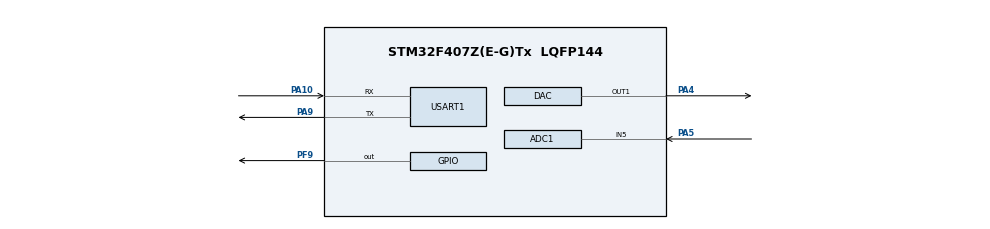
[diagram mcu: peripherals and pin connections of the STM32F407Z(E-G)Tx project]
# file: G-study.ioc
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ADC1.Channel-0\#ChannelRegularConversion=ADC_CHANNEL_5
ADC1.NbrOfConversionFlag=1
ADC1.Rank-0\#ChannelRegularConversion=1
ADC1.SamplingTime-0\#ChannelRegularConversion=ADC_SAMPLETIME_480CYCLES
ADC1.master=1
DAC.DAC_OutputBuffer=DAC_OUTPUTBUFFER_DISABLE
DAC.DAC_Trigger=DAC_TRIGGER_T6_TRGO
Dma.DAC1.0.Direction=DMA_MEMORY_TO_PERIPH
Dma.DAC1.0.FIFOMode=DMA_FIFOMODE_DISABLE
Dma.DAC1.0.Instance=DMA1_Stream5
Dma.DAC1.0.MemDataAlignment=DMA_MDATAALIGN_HALFWORD
Dma.DAC1.0.MemInc=DMA_MINC_ENABLE
Dma.DAC1.0.Mode=DMA_CIRCULAR
Dma.DAC1.0.PeriphDataAlignment=DMA_PDATAALIGN_HALFWORD
Dma.DAC1.0.PeriphInc=DMA_PINC_DISABLE
Dma.DAC1.0.Priority=DMA_PRIORITY_HIGH
Dma.Request0=DAC1
Mcu.Family=STM32F4
Mcu.Name=STM32F407Z(E-G)Tx
Mcu.Package=LQFP144
NVIC.DMA1_Stream5_IRQn=true\:0\:0\:false\:false\:true\:false\:true\:true
NVIC.PriorityGroup=NVIC_PRIORITYGROUP_4
NVIC.USART1_IRQn=true\:0\:0\:false\:false\:true\:true\:true\:true
PA10.Mode=Asynchronous
PA10.Signal=USART1_RX
PA4.Signal=COMP_DAC1_group
PA5.Signal=ADCx_IN5
PA9.Mode=Asynchronous
PA9.Signal=USART1_TX
PF9.PinState=GPIO_PIN_SET
PF9.Signal=GPIO_Output
PH0-OSC_IN.Mode=HSE-External-Oscillator
PH0-OSC_IN.Signal=RCC_OSC_IN
PH1-OSC_OUT.Mode=HSE-External-Oscillator
PH1-OSC_OUT.Signal=RCC_OSC_OUT
ProjectManager.HeapSize=0x200
ProjectManager.StackSize=0x400
ProjectManager.TargetToolchain=STM32CubeIDE
RCC.48MHZClocksFreq_Value=84000000
RCC.AHBFreq_Value=168000000
RCC.APB1CLKDivider=RCC_HCLK_DIV4
RCC.APB1Freq_Value=42000000
RCC.APB1TimFreq_Value=84000000
RCC.APB2CLKDivider=RCC_HCLK_DIV2
RCC.APB2Freq_Value=84000000
RCC.APB2TimFreq_Value=168000000
RCC.CortexFreq_Value=168000000
RCC.HCLKFreq_Value=168000000
RCC.HSE_VALUE=8000000
RCC.HSI_VALUE=16000000
RCC.LSE_VALUE=32768
RCC.PLLM=8
RCC.PLLN=336
RCC.PLLSourceVirtual=RCC_PLLSOURCE_HSE
RCC.SYSCLKFreq_VALUE=168000000
RCC.SYSCLKSource=RCC_SYSCLKSOURCE_PLLCLK
RCC.VCOOutputFreq_Value=336000000
SH.ADCx_IN5.0=ADC1_IN5,IN5
SH.COMP_DAC1_group.0=DAC_OUT1,DAC_OUT1
TIM6.AutoReloadPreload=TIM_AUTORELOAD_PRELOAD_ENABLE
TIM6.Period=99
TIM6.Prescaler=83
TIM6.TIM_MasterOutputTrigger=TIM_TRGO_UPDATE
USART1.VirtualMode=VM_ASYNC
VP_TIM6_VS_ClockSourceINT.Mode=Enable_Timer
board=custom

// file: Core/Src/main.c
/* USER CODE BEGIN Header */
/**
  ******************************************************************************
  * @file           : main.c
  * @brief          : Main program body
  ******************************************************************************
  * @attention
  *
  * Copyright (c) 2026 STMicroelectronics.
  * All rights reserved.
  *
  * This software is licensed under terms that can be found in the LICENSE file
  * in the root directory of this software component.
  * If no LICENSE file comes with this software, it is provided AS-IS.
  *
  ******************************************************************************
  */
/* USER CODE END Header */
#include "main.h"

ADC_HandleTypeDef hadc1;

DAC_HandleTypeDef hdac;
DMA_HandleTypeDef hdma_dac1;

TIM_HandleTypeDef htim6;

UART_HandleTypeDef huart1;

void SystemClock_Config(void);
static void MX_GPIO_Init(void);
static void MX_DMA_Init(void);
static void MX_DAC_Init(void);
static void MX_TIM6_Init(void);
static void MX_USART1_UART_Init(void);
static void MX_ADC1_Init(void);

int main(void)
{

/* USER CODE BEGIN 1 */
  RCC->AHB1ENR |= (1 << 5);
  GPIOF->MODER = (GPIOF->MODER & ~(3 << 18)) | (1 << 18);
  while(1) {
    GPIOF->ODR ^= (1 << 9);
    for(volatile int i = 0; i < 2000000; i++);
  }
  RCC->AHB1ENR |= (1 << 5);
  GPIOF->MODER = (GPIOF->MODER & ~(3 << 18)) | (1 << 18);
  GPIOF->ODR &= ~(1 << 9);

  /* USER CODE END 1 */

  /* MCU Configuration--------------------------------------------------------*/

  /* Reset of all peripherals, Initializes the Flash interface and the Systick. */
  HAL_Init();

  /* Configure the system clock */
  SystemClock_Config();

  /* Initialize all configured peripherals */
  MX_GPIO_Init();
  MX_DMA_Init();
  MX_DAC_Init();
  MX_TIM6_Init();
  MX_USART1_UART_Init();
  MX_ADC1_Init();
  /* USER CODE BEGIN 2 */
  RCC->AHB1ENR |= (1 << 5);
  GPIOF->MODER = (GPIOF->MODER & ~(3 << 18)) | (1 << 18);
  while(1) {
    GPIOF->ODR ^= (1 << 9);
    for(volatile int i = 0; i < 2000000; i++);
  }
  /* USER CODE END 2 */

  /* Infinite loop */
  while (1)
  {

  }
}

void SystemClock_Config(void)
{
  RCC_OscInitTypeDef RCC_OscInitStruct = {0};
  RCC_ClkInitTypeDef RCC_ClkInitStruct = {0};

  /** Configure the main internal regulator output voltage
  */
  __HAL_RCC_PWR_CLK_ENABLE();
  __HAL_PWR_VOLTAGESCALING_CONFIG(PWR_REGULATOR_VOLTAGE_SCALE1);

  /** Initializes the RCC Oscillators according to the specified parameters
  * in the RCC_OscInitTypeDef structure.
  */
  RCC_OscInitStruct.OscillatorType = RCC_OSCILLATORTYPE_HSI;
  RCC_OscInitStruct.HSIState = RCC_HSI_ON;
  RCC_OscInitStruct.HSICalibrationValue = RCC_HSICALIBRATION_DEFAULT;
  RCC_OscInitStruct.PLL.PLLState = RCC_PLL_NONE;
  if (HAL_RCC_OscConfig(&RCC_OscInitStruct) != HAL_OK)
  {
    Error_Handler();
  }

  /** Initializes the CPU, AHB and APB buses clocks
  */
  RCC_ClkInitStruct.ClockType = RCC_CLOCKTYPE_HCLK|RCC_CLOCKTYPE_SYSCLK
                              |RCC_CLOCKTYPE_PCLK1|RCC_CLOCKTYPE_PCLK2;
  RCC_ClkInitStruct.SYSCLKSource = RCC_SYSCLKSOURCE_HSI;
  RCC_ClkInitStruct.AHBCLKDivider = RCC_SYSCLK_DIV1;
  RCC_ClkInitStruct.APB1CLKDivider = RCC_HCLK_DIV4;
  RCC_ClkInitStruct.APB2CLKDivider = RCC_HCLK_DIV2;

  if (HAL_RCC_ClockConfig(&RCC_ClkInitStruct, FLASH_LATENCY_0) != HAL_OK)
  {
    Error_Handler();
  }
}

static void MX_ADC1_Init(void)
{

  ADC_ChannelConfTypeDef sConfig = {0};

  /** Configure the global features of the ADC (Clock, Resolution, Data Alignment and number of conversion)
  */
  hadc1.Instance = ADC1;
  hadc1.Init.ClockPrescaler = ADC_CLOCK_SYNC_PCLK_DIV2;
  hadc1.Init.Resolution = ADC_RESOLUTION_12B;
  hadc1.Init.ScanConvMode = DISABLE;
  hadc1.Init.ContinuousConvMode = DISABLE;
  hadc1.Init.DiscontinuousConvMode = DISABLE;
  hadc1.Init.ExternalTrigConvEdge = ADC_EXTERNALTRIGCONVEDGE_NONE;
  hadc1.Init.ExternalTrigConv = ADC_SOFTWARE_START;
  hadc1.Init.DataAlign = ADC_DATAALIGN_RIGHT;
  hadc1.Init.NbrOfConversion = 1;
  hadc1.Init.DMAContinuousRequests = DISABLE;
  hadc1.Init.EOCSelection = ADC_EOC_SINGLE_CONV;
  if (HAL_ADC_Init(&hadc1) != HAL_OK)
  {
    Error_Handler();
  }

  /** Configure for the selected ADC regular channel its corresponding rank in the sequencer and its sample time.
  */
  sConfig.Channel = ADC_CHANNEL_5;
  sConfig.Rank = 1;
  sConfig.SamplingTime = ADC_SAMPLETIME_480CYCLES;
  if (HAL_ADC_ConfigChannel(&hadc1, &sConfig) != HAL_OK)
  {
    Error_Handler();
  }

}

static void MX_DAC_Init(void)
{

  DAC_ChannelConfTypeDef sConfig = {0};

  /** DAC Initialization
  */
  hdac.Instance = DAC;
  if (HAL_DAC_Init(&hdac) != HAL_OK)
  {
    Error_Handler();
  }

  /** DAC channel OUT1 config
  */
  sConfig.DAC_Trigger = DAC_TRIGGER_T6_TRGO;
  sConfig.DAC_OutputBuffer = DAC_OUTPUTBUFFER_DISABLE;
  if (HAL_DAC_ConfigChannel(&hdac, &sConfig, DAC_CHANNEL_1) != HAL_OK)
  {
    Error_Handler();
  }

}

static void MX_TIM6_Init(void)
{

  TIM_MasterConfigTypeDef sMasterConfig = {0};

  htim6.Instance = TIM6;
  htim6.Init.Prescaler = 83;
  htim6.Init.CounterMode = TIM_COUNTERMODE_UP;
  htim6.Init.Period = 99;
  htim6.Init.AutoReloadPreload = TIM_AUTORELOAD_PRELOAD_ENABLE;
  if (HAL_TIM_Base_Init(&htim6) != HAL_OK)
  {
    Error_Handler();
  }
  sMasterConfig.MasterOutputTrigger = TIM_TRGO_UPDATE;
  sMasterConfig.MasterSlaveMode = TIM_MASTERSLAVEMODE_DISABLE;
  if (HAL_TIMEx_MasterConfigSynchronization(&htim6, &sMasterConfig) != HAL_OK)
  {
    Error_Handler();
  }

}

static void MX_USART1_UART_Init(void)
{

  huart1.Instance = USART1;
  huart1.Init.BaudRate = 115200;
  huart1.Init.WordLength = UART_WORDLENGTH_8B;
  huart1.Init.StopBits = UART_STOPBITS_1;
  huart1.Init.Parity = UART_PARITY_NONE;
  huart1.Init.Mode = UART_MODE_TX_RX;
  huart1.Init.HwFlowCtl = UART_HWCONTROL_NONE;
  huart1.Init.OverSampling = UART_OVERSAMPLING_16;
  if (HAL_UART_Init(&huart1) != HAL_OK)
  {
    Error_Handler();
  }

}

static void MX_DMA_Init(void)
{

  /* DMA controller clock enable */
  __HAL_RCC_DMA1_CLK_ENABLE();

  /* DMA interrupt init */
  /* DMA1_Stream5_IRQn interrupt configuration */
  HAL_NVIC_SetPriority(DMA1_Stream5_IRQn, 0, 0);
  HAL_NVIC_EnableIRQ(DMA1_Stream5_IRQn);

}

static void MX_GPIO_Init(void)
{
  GPIO_InitTypeDef GPIO_InitStruct = {0};

  /* GPIO Ports Clock Enable */
  __HAL_RCC_GPIOF_CLK_ENABLE();
  __HAL_RCC_GPIOH_CLK_ENABLE();
  __HAL_RCC_GPIOA_CLK_ENABLE();

  /*Configure GPIO pin Output Level */
  HAL_GPIO_WritePin(GPIOF, GPIO_PIN_9, GPIO_PIN_SET);

  /*Configure GPIO pin : PF9 */
  GPIO_InitStruct.Pin = GPIO_PIN_9;
  GPIO_InitStruct.Mode = GPIO_MODE_OUTPUT_PP;
  GPIO_InitStruct.Pull = GPIO_NOPULL;
  GPIO_InitStruct.Speed = GPIO_SPEED_FREQ_LOW;
  HAL_GPIO_Init(GPIOF, &GPIO_InitStruct);

}

void Error_Handler(void)
{
  /* USER CODE BEGIN Error_Handler_Debug */
  RCC->AHB1ENR |= (1 << 5);
  GPIOF->MODER = (GPIOF->MODER & ~(3 << 18)) | (1 << 18);
  while(1) {
    GPIOF->ODR ^= (1 << 9);
    for(volatile int i = 0; i < 2000000; i++);
  }
  /* USER CODE END Error_Handler_Debug */
}
